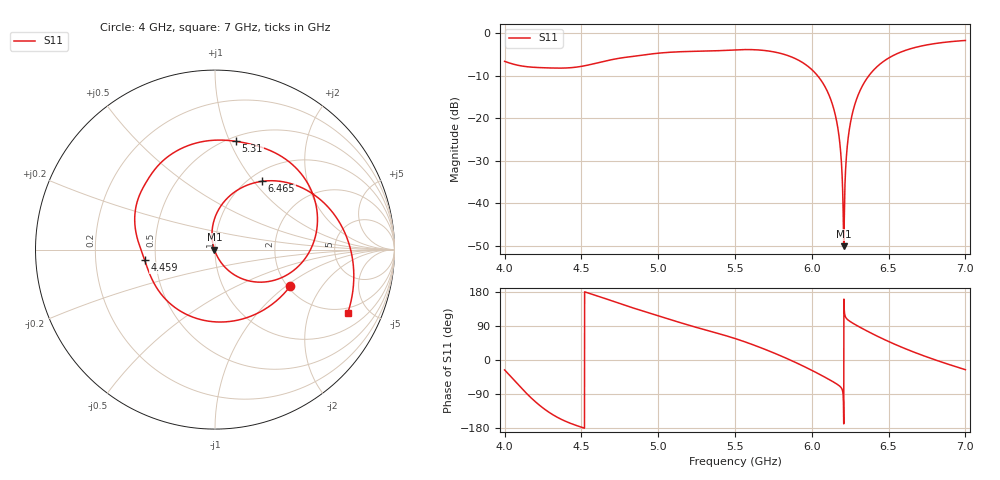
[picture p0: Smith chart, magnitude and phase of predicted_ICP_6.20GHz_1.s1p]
! ICP-predicted S11, target max centred GHz at -10 dB. Complex ensemble mean (passive and causal);
! its |S11| can differ slightly from the dB-domain mean reported in designs.csv.
!  Air_gap = 1.73mm
!  W_Patch = 14.83mm
!  L_Patch = 18.81mm
!  Sx = 0.47mm
!  Sy = 4.28mm
!  W_Patch1 = 13.39mm
!  WS = 1.04mm
!  Curve_Amp1 = 3.31mm
!  Extra = 7.23mm
# GHz S MA R 50
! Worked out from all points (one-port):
!   3001 points, 4 GHz to 7 GHz, reference 50 ohm
!   lowest |S11| = -50.1 dB at 6.208 GHz (marker M1), VSWR 1.01, Z = 49.7 - j0.0624 ohm
!   |S11| at or under -10 dB: 6.037 GHz to 6.372 GHz (334.4 MHz wide, 5.39 % of centre)
!   S11 on the Smith chart (normalised r, x): 4 GHz: 2.06, -1.08; 4.459 GHz: 0.43, -0.06; 5.31 GHz: 0.54, +1.05; 6.465 GHz: 1.14, +1.11; 7 GHz: 1.70, -3.67
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4  0.4658 -26.2
4.077  0.4227 -60.2
4.148  0.4024 -90.3
4.257  0.3914 -128.8
4.375  0.3881 -157.7
4.459  0.3967 -171.6
4.75  0.5077 148.9
4.937  0.5636 124.9
5.125  0.6022 100.9
5.31  0.6145 79.0
5.5  0.6359 56.7
5.711  0.6189 25.6
5.875  0.5185 -2.9
6.023  0.3386 -32.0
6.12  0.1724 -53.1
6.171  0.07381 -65.7
6.185  0.04596 -70.2
6.198  0.02001 -78.2
6.208  0.003136 -168.5
6.217  0.01881 116.1
6.232  0.04895 106.9
6.25  0.08516 101.4
6.282  0.1488 93.6
6.327  0.2354 83.5
6.465  0.4626 55.4
6.625  0.6404 27.2
6.806  0.7557 -0.0
7  0.8198 -25.5
